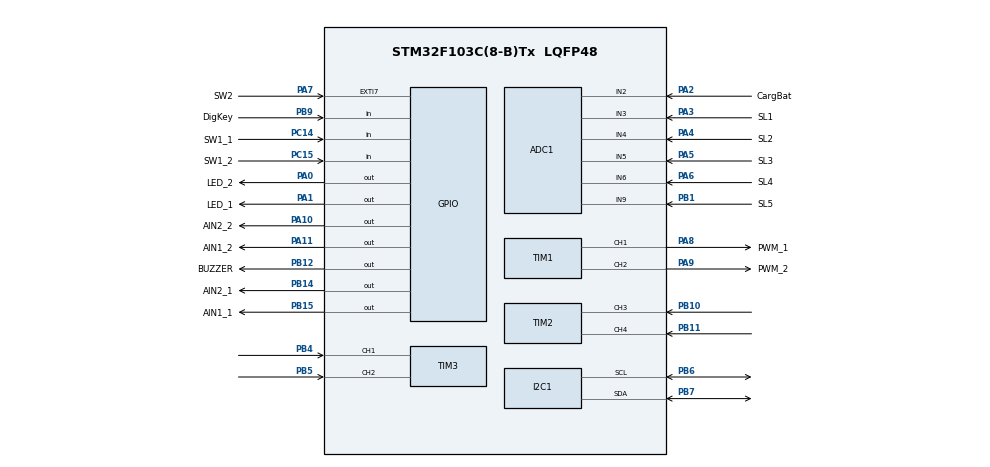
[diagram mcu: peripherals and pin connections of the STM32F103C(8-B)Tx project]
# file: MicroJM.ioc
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ADC1.Channel-0\#ChannelRegularConversion=ADC_CHANNEL_2
ADC1.NbrOfConversionFlag=1
ADC1.Rank-0\#ChannelRegularConversion=1
ADC1.SamplingTime-0\#ChannelRegularConversion=ADC_SAMPLETIME_1CYCLE_5
ADC1.master=1
Mcu.Family=STM32F1
Mcu.Name=STM32F103C(8-B)Tx
Mcu.Package=LQFP48
NVIC.ADC1_2_IRQn=true\:1\:0\:true\:false\:true\:true\:true\:true
NVIC.PriorityGroup=NVIC_PRIORITYGROUP_4
NVIC.TIM1_BRK_IRQn=true\:2\:0\:true\:false\:true\:true\:true\:true
NVIC.TIM1_CC_IRQn=true\:2\:0\:true\:false\:true\:true\:true\:true
NVIC.TIM1_TRG_COM_IRQn=true\:2\:0\:true\:false\:true\:true\:true\:true
NVIC.TIM1_UP_IRQn=true\:2\:0\:true\:false\:true\:true\:true\:true
PA0-WKUP.GPIO_Label=LED_2
PA0-WKUP.Signal=GPIO_Output
PA1.GPIO_Label=LED_1
PA1.Signal=GPIO_Output
PA10.GPIO_Label=AIN2_2
PA10.Signal=GPIO_Output
PA11.GPIO_Label=AIN1_2
PA11.Signal=GPIO_Output
PA13.Mode=Serial_Wire
PA13.Signal=SYS_JTMS-SWDIO
PA14.Mode=Serial_Wire
PA14.Signal=SYS_JTCK-SWCLK
PA2.GPIO_Label=CargBat
PA2.Signal=ADCx_IN2
PA3.GPIO_Label=SL1
PA3.Signal=ADCx_IN3
PA4.GPIO_Label=SL2
PA4.Signal=ADCx_IN4
PA5.GPIO_Label=SL3
PA5.Signal=ADCx_IN5
PA6.GPIO_Label=SL4
PA6.Signal=ADCx_IN6
PA7.GPIO_Label=SW2
PA7.Signal=GPXTI7
PA8.GPIO_Label=PWM_1
PA8.Signal=S_TIM1_CH1
PA9.GPIO_Label=PWM_2
PA9.Signal=S_TIM1_CH2
PB1.GPIO_Label=SL5
PB1.Signal=ADCx_IN9
PB10.Signal=S_TIM2_CH3
PB11.Signal=S_TIM2_CH4
PB12.GPIO_Label=BUZZER
PB12.Signal=GPIO_Output
PB14.GPIO_Label=AIN2_1
PB14.Signal=GPIO_Output
PB15.GPIO_Label=AIN1_1
PB15.Signal=GPIO_Output
PB4.Signal=S_TIM3_CH1
PB5.Signal=S_TIM3_CH2
PB6.Mode=I2C
PB6.Signal=I2C1_SCL
PB7.Mode=I2C
PB7.Signal=I2C1_SDA
PB9.GPIO_Label=DigKey
PB9.Signal=GPIO_Input
PC14-OSC32_IN.GPIO_Label=SW1_1
PC14-OSC32_IN.Signal=GPIO_Input
PC15-OSC32_OUT.GPIO_Label=SW1_2
PC15-OSC32_OUT.Signal=GPIO_Input
ProjectManager.HeapSize=0x200
ProjectManager.StackSize=0x400
ProjectManager.TargetToolchain=STM32CubeIDE
RCC.APB1Freq_Value=8000000
RCC.APB2Freq_Value=8000000
SH.ADCx_IN2.0=ADC1_IN2,IN2
SH.ADCx_IN3.0=ADC1_IN3,IN3
SH.ADCx_IN4.0=ADC1_IN4,IN4
SH.ADCx_IN5.0=ADC1_IN5,IN5
SH.ADCx_IN6.0=ADC1_IN6,IN6
SH.ADCx_IN9.0=ADC1_IN9,IN9
SH.S_TIM1_CH1.0=TIM1_CH1,PWM Generation1 CH1
SH.S_TIM1_CH2.0=TIM1_CH2,PWM Generation2 CH2
SH.S_TIM2_CH3.0=TIM2_CH3,Input_Capture3_from_TI3
SH.S_TIM2_CH4.0=TIM2_CH4,Input_Capture4_from_TI4
SH.S_TIM3_CH1.0=TIM3_CH1,Input_Capture1_from_TI1
SH.S_TIM3_CH2.0=TIM3_CH2,Input_Capture2_from_TI2
TIM1.Channel-PWM\ Generation1\ CH1=TIM_CHANNEL_1
TIM1.Channel-PWM\ Generation2\ CH2=TIM_CHANNEL_2
TIM2.Channel-Input_Capture3_from_TI3=TIM_CHANNEL_3
TIM2.Channel-Input_Capture4_from_TI4=TIM_CHANNEL_4
TIM3.Channel-Input_Capture1_from_TI1=TIM_CHANNEL_1
TIM3.Channel-Input_Capture2_from_TI2=TIM_CHANNEL_2
VP_TIM1_VS_ClockSourceINT.Mode=Internal
board=custom

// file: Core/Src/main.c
/* USER CODE BEGIN Header */
/**
  ******************************************************************************
  * @file           : main.c
  * @brief          : Main program body
  ******************************************************************************
  * @attention
  *
  * Copyright (c) 2026 STMicroelectronics.
  * All rights reserved.
  *
  * This software is licensed under terms that can be found in the LICENSE file
  * in the root directory of this software component.
  * If no LICENSE file comes with this software, it is provided AS-IS.
  *
  ******************************************************************************
  */
/* USER CODE END Header */
#include "main.h"

/* USER CODE BEGIN Includes */
#include "app_main.h"
#include "imu.h"
#include "app3.h"
#include "sensors.h"
#include "motor3.h"
#include "sensor_test.h"
/* USER CODE END Includes */

ADC_HandleTypeDef hadc1;
extern DMA_HandleTypeDef hdma_adc1;

I2C_HandleTypeDef hi2c1;

TIM_HandleTypeDef htim1;
TIM_HandleTypeDef htim2;
TIM_HandleTypeDef htim3;

void SystemClock_Config(void);
static void MX_GPIO_Init(void);
static void MX_DMA_Init(void);
static void MX_ADC1_Init(void);
static void MX_I2C1_Init(void);
static void MX_TIM1_Init(void);
static void MX_TIM2_Init(void);
static void MX_TIM3_Init(void);

int main(void)
{

  /* MCU Configuration--------------------------------------------------------*/

  /* Reset of all peripherals, Initializes the Flash interface and the Systick. */
  HAL_Init();

  /* Configure the system clock */
  SystemClock_Config();

  /* Initialize all configured peripherals */
  MX_GPIO_Init();
  MX_DMA_Init();
  MX_ADC1_Init();
  MX_I2C1_Init();
  MX_TIM1_Init();
  MX_TIM2_Init();
  MX_TIM3_Init();
  /* USER CODE BEGIN 2 */

  /* =========================================================================
   * ESCOLHA DO MODO DE EXECUCAO DO MICROJM
   * =========================================================================
   * OPCAO A: app_init() e app_loop() (ARQUITETURA COMPLETA fw_micromouse_f411)
   *          Escalonador cooperativo sem RTOS (1kHz controle, 200Hz sensores/IMU,
   *          100Hz navegacao, 10Hz telemetria).
   *          O modo ativo e' escolhido em Core/Inc/app_main.h pelo define APP_MODE:
   *            - APP_MODE_MOTOR_TEST   (teste de fiacao, sentido e encoder)
   *            - APP_MODE_SENSOR_CAL   (calibracao dos 5 sensores Sharp IR)
   *            - APP_MODE_TURN_CAL     (calibracao do giro de 90 graus)
   *            - APP_MODE_IMU_TEST     (teste e calibracao do MPU-6050)
   *            - APP_MODE_MAZE         (seguidor de paredes / labirinto)
   *            - APP_MODE_SOLVE        (flood fill autonomo: explora e corre)
   *
   * OPCAO B: sensor_test_init() e sensor_test_loop()
   *          Teste conjunto em bancada de todos os 5 ADCs, IMU, PWM e Encoders
   *          visivel no Live Expressions.
   * ========================================================================= */

  /* Para rodar o fw_micromouse_f411 adaptado para Blue Pill: */
  app_init();

  /* Para voltar ao teste rapido de bancada dos sensores/IMU, use: */
  // sensor_test_init();

  /* USER CODE END 2 */

  /* Infinite loop */
  while (1)
  {

    /* USER CODE BEGIN 3 */
    app_loop();

    /* Se estiver usando o teste de bancada: */
    // sensor_test_loop();
  }
  /* USER CODE END 3 */
}

void SystemClock_Config(void)
{
  RCC_OscInitTypeDef RCC_OscInitStruct = {0};
  RCC_ClkInitTypeDef RCC_ClkInitStruct = {0};
  RCC_PeriphCLKInitTypeDef PeriphClkInit = {0};

  /** Initializes the RCC Oscillators according to the specified parameters
  * in the RCC_OscInitTypeDef structure.
  */
  RCC_OscInitStruct.OscillatorType = RCC_OSCILLATORTYPE_HSI;
  RCC_OscInitStruct.HSIState = RCC_HSI_ON;
  RCC_OscInitStruct.HSICalibrationValue = RCC_HSICALIBRATION_DEFAULT;
  RCC_OscInitStruct.PLL.PLLState = RCC_PLL_ON;
  RCC_OscInitStruct.PLL.PLLSource = RCC_PLLSOURCE_HSI_DIV2;
  RCC_OscInitStruct.PLL.PLLMUL = RCC_PLL_MUL16;
  if (HAL_RCC_OscConfig(&RCC_OscInitStruct) != HAL_OK)
  {
    Error_Handler();
  }

  /** Initializes the CPU, AHB and APB buses clocks
  */
  RCC_ClkInitStruct.ClockType = RCC_CLOCKTYPE_HCLK|RCC_CLOCKTYPE_SYSCLK
                              |RCC_CLOCKTYPE_PCLK1|RCC_CLOCKTYPE_PCLK2;
  RCC_ClkInitStruct.SYSCLKSource = RCC_SYSCLKSOURCE_PLLCLK;
  RCC_ClkInitStruct.AHBCLKDivider = RCC_SYSCLK_DIV1;
  RCC_ClkInitStruct.APB1CLKDivider = RCC_HCLK_DIV2;
  RCC_ClkInitStruct.APB2CLKDivider = RCC_HCLK_DIV1;

  if (HAL_RCC_ClockConfig(&RCC_ClkInitStruct, FLASH_LATENCY_2) != HAL_OK)
  {
    Error_Handler();
  }
  PeriphClkInit.PeriphClockSelection = RCC_PERIPHCLK_ADC;
  PeriphClkInit.AdcClockSelection = RCC_ADCPCLK2_DIV6;
  if (HAL_RCCEx_PeriphCLKConfig(&PeriphClkInit) != HAL_OK)
  {
    Error_Handler();
  }
}

static void MX_ADC1_Init(void)
{

  ADC_ChannelConfTypeDef sConfig = {0};

  /** Common config
  */
  hadc1.Instance = ADC1;
  hadc1.Init.ScanConvMode = ADC_SCAN_ENABLE;
  hadc1.Init.ContinuousConvMode = ENABLE;
  hadc1.Init.DiscontinuousConvMode = DISABLE;
  hadc1.Init.ExternalTrigConv = ADC_SOFTWARE_START;
  hadc1.Init.DataAlign = ADC_DATAALIGN_RIGHT;
  hadc1.Init.NbrOfConversion = 6;
  if (HAL_ADC_Init(&hadc1) != HAL_OK)
  {
    Error_Handler();
  }

  /** Configure Regular Channels (match original working order)
   *  Rank 1 = ADC_CHANNEL_4  (PA4 – SL2 sharp esquerda)
   *  Rank 2 = ADC_CHANNEL_5  (PA5 – SL3 borda direita)
   *  Rank 3 = ADC_CHANNEL_3  (PA3 – SL1 sharp direita)
   *  Rank 4 = ADC_CHANNEL_6  (PA6 – SL4 borda esquerda)
   *  Rank 5 = ADC_CHANNEL_2  (PA2 – CargBat bateria)
   *  Rank 6 = ADC_CHANNEL_9  (PB1 – SL5 sensor central)
  */
  sConfig.SamplingTime = ADC_SAMPLETIME_28CYCLES_5;

  sConfig.Channel = ADC_CHANNEL_4;
  sConfig.Rank = ADC_REGULAR_RANK_1;
  if (HAL_ADC_ConfigChannel(&hadc1, &sConfig) != HAL_OK)
  {
    Error_Handler();
  }

  sConfig.Channel = ADC_CHANNEL_5;
  sConfig.Rank = ADC_REGULAR_RANK_2;
  if (HAL_ADC_ConfigChannel(&hadc1, &sConfig) != HAL_OK)
  {
    Error_Handler();
  }

  sConfig.Channel = ADC_CHANNEL_3;
  sConfig.Rank = ADC_REGULAR_RANK_3;
  if (HAL_ADC_ConfigChannel(&hadc1, &sConfig) != HAL_OK)
  {
    Error_Handler();
  }

  sConfig.Channel = ADC_CHANNEL_6;
  sConfig.Rank = ADC_REGULAR_RANK_4;
  if (HAL_ADC_ConfigChannel(&hadc1, &sConfig) != HAL_OK)
  {
    Error_Handler();
  }

  sConfig.Channel = ADC_CHANNEL_2;
  sConfig.Rank = ADC_REGULAR_RANK_5;
  if (HAL_ADC_ConfigChannel(&hadc1, &sConfig) != HAL_OK)
  {
    Error_Handler();
  }

  sConfig.Channel = ADC_CHANNEL_9;
  sConfig.Rank = ADC_REGULAR_RANK_6;
  if (HAL_ADC_ConfigChannel(&hadc1, &sConfig) != HAL_OK)
  {
    Error_Handler();
  }

}

static void MX_I2C1_Init(void)
{

  hi2c1.Instance = I2C1;
  hi2c1.Init.ClockSpeed = 100000;
  hi2c1.Init.DutyCycle = I2C_DUTYCYCLE_2;
  hi2c1.Init.OwnAddress1 = 0;
  hi2c1.Init.AddressingMode = I2C_ADDRESSINGMODE_7BIT;
  hi2c1.Init.DualAddressMode = I2C_DUALADDRESS_DISABLE;
  hi2c1.Init.OwnAddress2 = 0;
  hi2c1.Init.GeneralCallMode = I2C_GENERALCALL_DISABLE;
  hi2c1.Init.NoStretchMode = I2C_NOSTRETCH_DISABLE;
  if (HAL_I2C_Init(&hi2c1) != HAL_OK)
  {
    Error_Handler();
  }

}

static void MX_TIM1_Init(void)
{

  TIM_ClockConfigTypeDef sClockSourceConfig = {0};
  TIM_MasterConfigTypeDef sMasterConfig = {0};
  TIM_OC_InitTypeDef sConfigOC = {0};
  TIM_BreakDeadTimeConfigTypeDef sBreakDeadTimeConfig = {0};

  htim1.Instance = TIM1;
  htim1.Init.Prescaler = 63;
  htim1.Init.CounterMode = TIM_COUNTERMODE_UP;
  htim1.Init.Period = 19999;
  htim1.Init.ClockDivision = TIM_CLOCKDIVISION_DIV1;
  htim1.Init.RepetitionCounter = 0;
  htim1.Init.AutoReloadPreload = TIM_AUTORELOAD_PRELOAD_DISABLE;
  if (HAL_TIM_Base_Init(&htim1) != HAL_OK)
  {
    Error_Handler();
  }
  sClockSourceConfig.ClockSource = TIM_CLOCKSOURCE_INTERNAL;
  if (HAL_TIM_ConfigClockSource(&htim1, &sClockSourceConfig) != HAL_OK)
  {
    Error_Handler();
  }
  if (HAL_TIM_PWM_Init(&htim1) != HAL_OK)
  {
    Error_Handler();
  }
  sMasterConfig.MasterOutputTrigger = TIM_TRGO_RESET;
  sMasterConfig.MasterSlaveMode = TIM_MASTERSLAVEMODE_DISABLE;
  if (HAL_TIMEx_MasterConfigSynchronization(&htim1, &sMasterConfig) != HAL_OK)
  {
    Error_Handler();
  }
  sConfigOC.OCMode = TIM_OCMODE_PWM1;
  sConfigOC.Pulse = 19999;
  sConfigOC.OCPolarity = TIM_OCPOLARITY_HIGH;
  sConfigOC.OCNPolarity = TIM_OCNPOLARITY_HIGH;
  sConfigOC.OCFastMode = TIM_OCFAST_DISABLE;
  sConfigOC.OCIdleState = TIM_OCIDLESTATE_RESET;
  sConfigOC.OCNIdleState = TIM_OCNIDLESTATE_RESET;
  if (HAL_TIM_PWM_ConfigChannel(&htim1, &sConfigOC, TIM_CHANNEL_1) != HAL_OK)
  {
    Error_Handler();
  }
  if (HAL_TIM_PWM_ConfigChannel(&htim1, &sConfigOC, TIM_CHANNEL_2) != HAL_OK)
  {
    Error_Handler();
  }
  sBreakDeadTimeConfig.OffStateRunMode = TIM_OSSR_DISABLE;
  sBreakDeadTimeConfig.OffStateIDLEMode = TIM_OSSI_DISABLE;
  sBreakDeadTimeConfig.LockLevel = TIM_LOCKLEVEL_OFF;
  sBreakDeadTimeConfig.DeadTime = 0;
  sBreakDeadTimeConfig.BreakState = TIM_BREAK_DISABLE;
  sBreakDeadTimeConfig.BreakPolarity = TIM_BREAKPOLARITY_HIGH;
  sBreakDeadTimeConfig.AutomaticOutput = TIM_AUTOMATICOUTPUT_DISABLE;
  if (HAL_TIMEx_ConfigBreakDeadTime(&htim1, &sBreakDeadTimeConfig) != HAL_OK)
  {
    Error_Handler();
  }
  HAL_TIM_MspPostInit(&htim1);

}

static void MX_TIM2_Init(void)
{

  TIM_Encoder_InitTypeDef sEncoderConfig = {0};
  TIM_MasterConfigTypeDef sMasterConfig = {0};

  htim2.Instance = TIM2;
  htim2.Init.Prescaler = 0;
  htim2.Init.CounterMode = TIM_COUNTERMODE_UP;
  htim2.Init.Period = 65535;
  htim2.Init.ClockDivision = TIM_CLOCKDIVISION_DIV1;
  htim2.Init.AutoReloadPreload = TIM_AUTORELOAD_PRELOAD_DISABLE;

  // Encoder Mode: TI1 = CH1 (PA15) e TI2 = CH2 (PB3) — motor esquerdo (TIM2 remap completo)
  sEncoderConfig.EncoderMode = TIM_ENCODERMODE_TI12;
  sEncoderConfig.IC1Polarity = TIM_ICPOLARITY_RISING;
  sEncoderConfig.IC1Selection = TIM_ICSELECTION_DIRECTTI;
  sEncoderConfig.IC1Prescaler = TIM_ICPSC_DIV1;
  sEncoderConfig.IC1Filter = 4;
  sEncoderConfig.IC2Polarity = TIM_ICPOLARITY_RISING;
  sEncoderConfig.IC2Selection = TIM_ICSELECTION_DIRECTTI;
  sEncoderConfig.IC2Prescaler = TIM_ICPSC_DIV1;
  sEncoderConfig.IC2Filter = 4;
  if (HAL_TIM_Encoder_Init(&htim2, &sEncoderConfig) != HAL_OK)
  {
    Error_Handler();
  }
  sMasterConfig.MasterOutputTrigger = TIM_TRGO_RESET;
  sMasterConfig.MasterSlaveMode = TIM_MASTERSLAVEMODE_DISABLE;
  if (HAL_TIMEx_MasterConfigSynchronization(&htim2, &sMasterConfig) != HAL_OK)
  {
    Error_Handler();
  }

}

static void MX_TIM3_Init(void)
{

  TIM_Encoder_InitTypeDef sEncoderConfig = {0};
  TIM_MasterConfigTypeDef sMasterConfig = {0};

  htim3.Instance = TIM3;
  htim3.Init.Prescaler = 0;
  htim3.Init.CounterMode = TIM_COUNTERMODE_UP;
  htim3.Init.Period = 65535;
  htim3.Init.ClockDivision = TIM_CLOCKDIVISION_DIV1;
  htim3.Init.AutoReloadPreload = TIM_AUTORELOAD_PRELOAD_DISABLE;

  // Encoder Mode: TI1 = CH1 (PB4) e TI2 = CH2 (PB5) — motor direito
  sEncoderConfig.EncoderMode = TIM_ENCODERMODE_TI12;
  sEncoderConfig.IC1Polarity = TIM_ICPOLARITY_RISING;
  sEncoderConfig.IC1Selection = TIM_ICSELECTION_DIRECTTI;
  sEncoderConfig.IC1Prescaler = TIM_ICPSC_DIV1;
  sEncoderConfig.IC1Filter = 4;
  sEncoderConfig.IC2Polarity = TIM_ICPOLARITY_RISING;
  sEncoderConfig.IC2Selection = TIM_ICSELECTION_DIRECTTI;
  sEncoderConfig.IC2Prescaler = TIM_ICPSC_DIV1;
  sEncoderConfig.IC2Filter = 4;
  if (HAL_TIM_Encoder_Init(&htim3, &sEncoderConfig) != HAL_OK)
  {
    Error_Handler();
  }
  sMasterConfig.MasterOutputTrigger = TIM_TRGO_RESET;
  sMasterConfig.MasterSlaveMode = TIM_MASTERSLAVEMODE_DISABLE;
  if (HAL_TIMEx_MasterConfigSynchronization(&htim3, &sMasterConfig) != HAL_OK)
  {
    Error_Handler();
  }

}

static void MX_DMA_Init(void)
{

  /* DMA controller clock enable */
  __HAL_RCC_DMA1_CLK_ENABLE();

  /* DMA interrupt init */
  /* DMA1_Channel1_IRQn interrupt configuration */
  HAL_NVIC_SetPriority(DMA1_Channel1_IRQn, 0, 0);
  HAL_NVIC_EnableIRQ(DMA1_Channel1_IRQn);

}

static void MX_GPIO_Init(void)
{
  GPIO_InitTypeDef GPIO_InitStruct = {0};

  /* GPIO Ports Clock Enable */
  __HAL_RCC_GPIOC_CLK_ENABLE();
  __HAL_RCC_GPIOA_CLK_ENABLE();
  __HAL_RCC_GPIOB_CLK_ENABLE();

  /*Configure GPIO pin Output Level */
  HAL_GPIO_WritePin(GPIOA, LED_2_Pin|LED_1_Pin, GPIO_PIN_RESET);

  /*Configure GPIO pin Output Level */
  HAL_GPIO_WritePin(BUZZER_GPIO_Port, BUZZER_Pin, GPIO_PIN_RESET);

  /*Configure GPIO pin Output Level */
  HAL_GPIO_WritePin(GPIOB, AIN2_1_Pin|AIN1_1_Pin, GPIO_PIN_SET);

  /*Configure GPIO pin Output Level */
  HAL_GPIO_WritePin(GPIOA, AIN2_2_Pin|AIN1_2_Pin, GPIO_PIN_SET);

  /*Configure GPIO pins : SW1_1_Pin SW1_2_Pin */
  GPIO_InitStruct.Pin = SW1_1_Pin|SW1_2_Pin;
  GPIO_InitStruct.Mode = GPIO_MODE_INPUT;
  GPIO_InitStruct.Pull = GPIO_PULLUP;
  HAL_GPIO_Init(GPIOC, &GPIO_InitStruct);

  /*Configure GPIO pins : LED_2_Pin LED_1_Pin AIN2_2_Pin AIN1_2_Pin */
  GPIO_InitStruct.Pin = LED_2_Pin|LED_1_Pin|AIN2_2_Pin|AIN1_2_Pin;
  GPIO_InitStruct.Mode = GPIO_MODE_OUTPUT_PP;
  GPIO_InitStruct.Pull = GPIO_NOPULL;
  GPIO_InitStruct.Speed = GPIO_SPEED_FREQ_LOW;
  HAL_GPIO_Init(GPIOA, &GPIO_InitStruct);

  /*Configure GPIO pin : SW2_Pin */
  GPIO_InitStruct.Pin = SW2_Pin;
  GPIO_InitStruct.Mode = GPIO_MODE_IT_FALLING;
  GPIO_InitStruct.Pull = GPIO_PULLUP;
  HAL_GPIO_Init(SW2_GPIO_Port, &GPIO_InitStruct);

  /*Configure GPIO pins : BUZZER_Pin AIN2_1_Pin AIN1_1_Pin */
  GPIO_InitStruct.Pin = BUZZER_Pin|AIN2_1_Pin|AIN1_1_Pin;
  GPIO_InitStruct.Mode = GPIO_MODE_OUTPUT_PP;
  GPIO_InitStruct.Pull = GPIO_NOPULL;
  GPIO_InitStruct.Speed = GPIO_SPEED_FREQ_LOW;
  HAL_GPIO_Init(GPIOB, &GPIO_InitStruct);

  /*Configure GPIO pin : DigKey_Pin */
  GPIO_InitStruct.Pin = DigKey_Pin;
  GPIO_InitStruct.Mode = GPIO_MODE_INPUT;
  GPIO_InitStruct.Pull = GPIO_NOPULL;
  HAL_GPIO_Init(DigKey_GPIO_Port, &GPIO_InitStruct);

  /* EXTI interrupt init*/
  HAL_NVIC_SetPriority(EXTI9_5_IRQn, 2, 0);
  HAL_NVIC_EnableIRQ(EXTI9_5_IRQn);

}

void Error_Handler(void)
{
  /* USER CODE BEGIN Error_Handler_Debug */
  /* User can add his own implementation to report the HAL error return state */
  __disable_irq();
  /* Para os motores (antes eles seguiam com o ultimo PWM). So' se o TIM1 ja'
   * foi configurado -- senao o handle ainda esta' vazio. */
  if (htim1.Instance != NULL)
  {
    app_emergency_stop();
  }
  while (1)
  {
  }
  /* USER CODE END Error_Handler_Debug */
}
